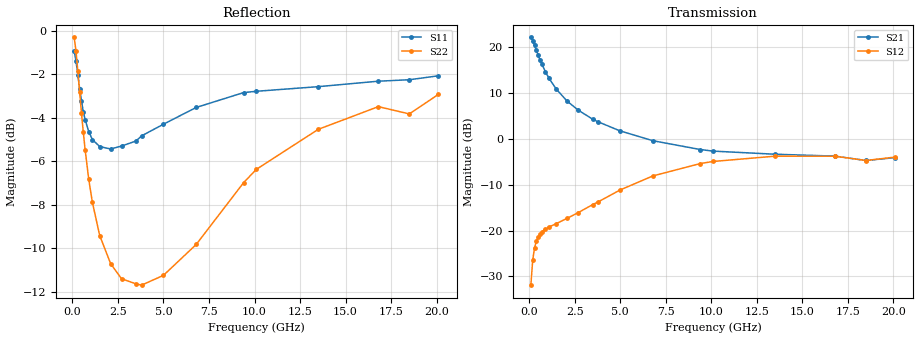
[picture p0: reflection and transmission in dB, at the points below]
!  Infineon Technologies AG
! BFR380L3 , PF131585-7, No.6, Th 09.10.01, soldered on pcb-board, measured with PP GSG850
!  Vce=6.0 V,  Ic=4.0 mA
! Common Emitter S-Parameters:  15. November 2001
#  GHz  S  MA  R  50
! f  S11  S21  S12  S22
! GHz  Mag  Ang  Mag  Ang  Mag  Ang  Mag  Ang
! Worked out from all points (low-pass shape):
!   201 points, 100 MHz to 20.1 GHz, reference 50 ohm
!   highest |S21| = 22.17 dB at 100 MHz (marker M1); lowest = -4.7 dB at 18.5 GHz (marker M2)
!   |S21| within 3 dB of the highest: start of sweep to 421.2 MHz
!   lowest |S11| = -5.4 dB at 2.1 GHz (marker M3), VSWR 3.30, Z = 15.2 - j0.573 ohm
!   |S11| at or under -10 dB: nowhere
!   |S22| runs from -11.7 to -0.3 dB; largest |S21 - S12| = 13
!   S11 on the Smith chart (normalised r, x): 100 MHz: 1.28, -4.60; 400 MHz: 0.37, -1.17; 1.1 GHz: 0.31, -0.33; 3.8 GHz: 0.29, +0.28; 9.4 GHz: 0.36, +1.06; 20.1 GHz: 0.98, +2.53
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0.1  0.8975 -22.9  12.84 164.3  0.02545 75.5  0.9652 -12.7
0.2  0.8508 -43.6  11.72 150.5  0.04774 67.2  0.8958 -23.9
0.3  0.7919 -62.3  10.52 138.7  0.06469 58.6  0.8068 -32.9
0.4  0.7354 -77.8  9.324 129.1  0.07637 52.2  0.7214 -39.7
0.5  0.6899 -91.4  8.258 121.2  0.08509 48.0  0.6469 -44.9
0.6  0.6511 -102.7  7.345 114.7  0.0913 44.8  0.5841 -48.8
0.7  0.6248 -112.4  6.593 109.2  0.09635 42.5  0.5324 -51.8
0.9  0.5857 -128.3  5.411 100.4  0.1036 40.2  0.4551 -56.1
1.1  0.5622 -140.6  4.58 93.4  0.1096 39.4  0.4029 -59.3
1.5  0.5415 -159.1  3.49 82.4  0.1195 40.3  0.3383 -63.8
2.1  0.5348 -178.6  2.579 69.5  0.1366 43.8  0.2915 -70.8
2.7  0.5431 166.8  2.065 58.8  0.1574 47.2  0.2691 -79.2
3.5  0.558 151.1  1.641 46.5  0.1925 50.3  0.2619 -91.7
3.8  0.5732 146.3  1.537 42.5  0.2065 50.8  0.2602 -98.1
5  0.6096 128.2  1.225 27.7  0.2777 49.7  0.274 -121.4
6.8  0.6662 106.2  0.9575 11.1  0.3955 41.1  0.3227 -159.4
9.400001  0.7207 83.1  0.7675 -3.6  0.5394 22.8  0.4474 156.5
10.1  0.7257 77.7  0.7376 -6.5  0.5684 17.5  0.4801 146.2
13.5  0.7437 59.5  0.6822 -19.7  0.6492 -6.5  0.5933 107.8
16.8  0.7655 47.6  0.6503 -31.2  0.6487 -23.9  0.6691 82.1
18.5  0.7714 45.5  0.5826 -38.8  0.5825 -32.5  0.6438 75.3
20.1  0.7877 38.5  0.6264 -42.1  0.6347 -38.0  0.714 64.1
